VERSION 5.7 ;
BUSBITCHARS "[]" ;
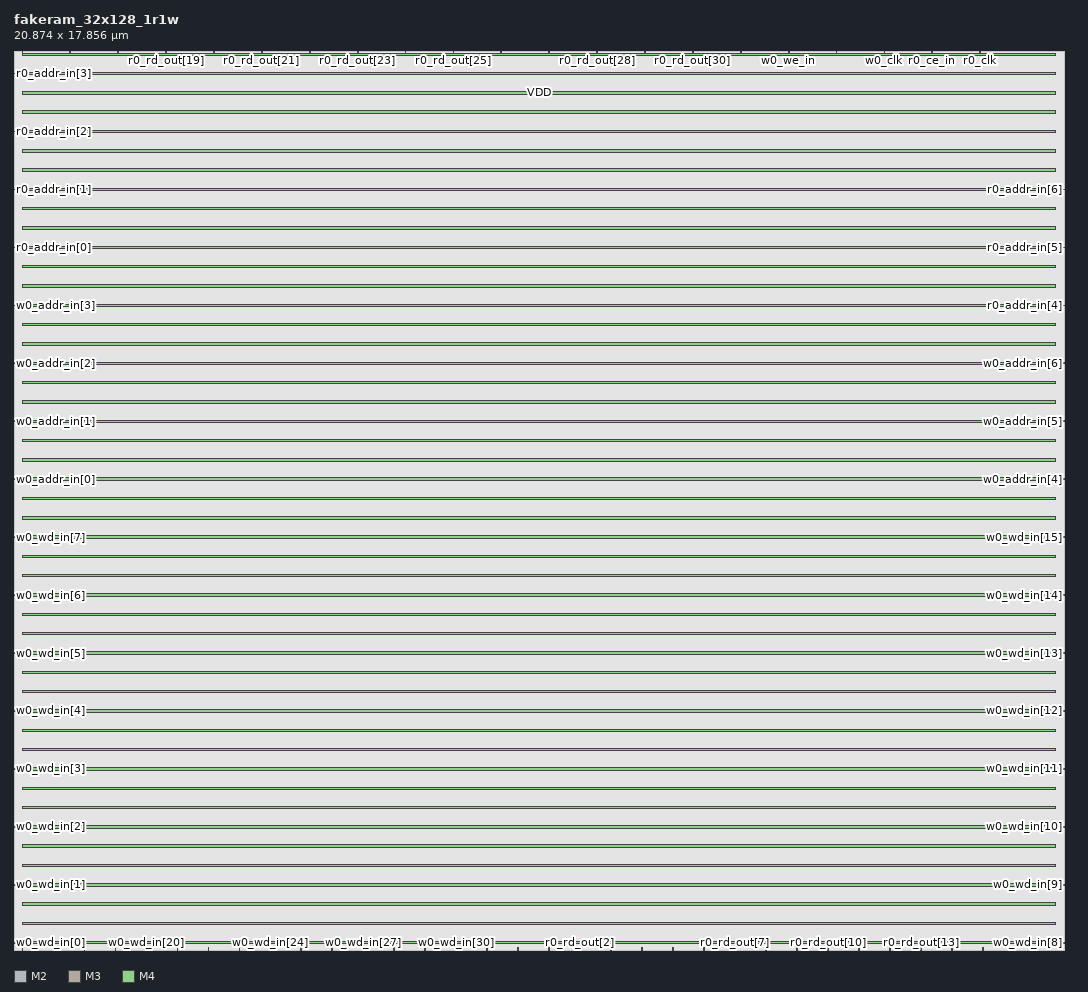
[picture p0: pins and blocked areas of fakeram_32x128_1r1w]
MACRO fakeram_32x128_1r1w
  FOREIGN fakeram_32x128_1r1w 0 0 ;
  SYMMETRY X Y R90 ;
  SIZE 20.874 BY 17.856 ;
  CLASS BLOCK ;
  PIN w0_wd_in[0]
    DIRECTION INPUT ;
    USE SIGNAL ;
    SHAPE ABUTMENT ;
    PORT
      LAYER M2 ;
      RECT 0.000 0.138 0.036 0.150 ;
    END
  END w0_wd_in[0]
  PIN w0_wd_in[1]
    DIRECTION INPUT ;
    USE SIGNAL ;
    SHAPE ABUTMENT ;
    PORT
      LAYER M2 ;
      RECT 0.000 1.290 0.036 1.302 ;
    END
  END w0_wd_in[1]
  PIN w0_wd_in[2]
    DIRECTION INPUT ;
    USE SIGNAL ;
    SHAPE ABUTMENT ;
    PORT
      LAYER M2 ;
      RECT 0.000 2.442 0.036 2.454 ;
    END
  END w0_wd_in[2]
  PIN w0_wd_in[3]
    DIRECTION INPUT ;
    USE SIGNAL ;
    SHAPE ABUTMENT ;
    PORT
      LAYER M2 ;
      RECT 0.000 3.594 0.036 3.606 ;
    END
  END w0_wd_in[3]
  PIN w0_wd_in[4]
    DIRECTION INPUT ;
    USE SIGNAL ;
    SHAPE ABUTMENT ;
    PORT
      LAYER M2 ;
      RECT 0.000 4.746 0.036 4.758 ;
    END
  END w0_wd_in[4]
  PIN w0_wd_in[5]
    DIRECTION INPUT ;
    USE SIGNAL ;
    SHAPE ABUTMENT ;
    PORT
      LAYER M2 ;
      RECT 0.000 5.898 0.036 5.910 ;
    END
  END w0_wd_in[5]
  PIN w0_wd_in[6]
    DIRECTION INPUT ;
    USE SIGNAL ;
    SHAPE ABUTMENT ;
    PORT
      LAYER M2 ;
      RECT 0.000 7.050 0.036 7.062 ;
    END
  END w0_wd_in[6]
  PIN w0_wd_in[7]
    DIRECTION INPUT ;
    USE SIGNAL ;
    SHAPE ABUTMENT ;
    PORT
      LAYER M2 ;
      RECT 0.000 8.202 0.036 8.214 ;
    END
  END w0_wd_in[7]
  PIN w0_wd_in[8]
    DIRECTION INPUT ;
    USE SIGNAL ;
    SHAPE ABUTMENT ;
    PORT
      LAYER M2 ;
      RECT 20.838 0.138 20.874 0.150 ;
    END
  END w0_wd_in[8]
  PIN w0_wd_in[9]
    DIRECTION INPUT ;
    USE SIGNAL ;
    SHAPE ABUTMENT ;
    PORT
      LAYER M2 ;
      RECT 20.838 1.290 20.874 1.302 ;
    END
  END w0_wd_in[9]
  PIN w0_wd_in[10]
    DIRECTION INPUT ;
    USE SIGNAL ;
    SHAPE ABUTMENT ;
    PORT
      LAYER M2 ;
      RECT 20.838 2.442 20.874 2.454 ;
    END
  END w0_wd_in[10]
  PIN w0_wd_in[11]
    DIRECTION INPUT ;
    USE SIGNAL ;
    SHAPE ABUTMENT ;
    PORT
      LAYER M2 ;
      RECT 20.838 3.594 20.874 3.606 ;
    END
  END w0_wd_in[11]
  PIN w0_wd_in[12]
    DIRECTION INPUT ;
    USE SIGNAL ;
    SHAPE ABUTMENT ;
    PORT
      LAYER M2 ;
      RECT 20.838 4.746 20.874 4.758 ;
    END
  END w0_wd_in[12]
  PIN w0_wd_in[13]
    DIRECTION INPUT ;
    USE SIGNAL ;
    SHAPE ABUTMENT ;
    PORT
      LAYER M2 ;
      RECT 20.838 5.898 20.874 5.910 ;
    END
  END w0_wd_in[13]
  PIN w0_wd_in[14]
    DIRECTION INPUT ;
    USE SIGNAL ;
    SHAPE ABUTMENT ;
    PORT
      LAYER M2 ;
      RECT 20.838 7.050 20.874 7.062 ;
    END
  END w0_wd_in[14]
  PIN w0_wd_in[15]
    DIRECTION INPUT ;
    USE SIGNAL ;
    SHAPE ABUTMENT ;
    PORT
      LAYER M2 ;
      RECT 20.838 8.202 20.874 8.214 ;
    END
  END w0_wd_in[15]
  PIN w0_wd_in[16]
    DIRECTION INPUT ;
    USE SIGNAL ;
    SHAPE ABUTMENT ;
    PORT
      LAYER M3 ;
      RECT 0.161 0.000 0.175 0.042 ;
    END
  END w0_wd_in[16]
  PIN w0_wd_in[17]
    DIRECTION INPUT ;
    USE SIGNAL ;
    SHAPE ABUTMENT ;
    PORT
      LAYER M3 ;
      RECT 0.777 0.000 0.791 0.042 ;
    END
  END w0_wd_in[17]
  PIN w0_wd_in[18]
    DIRECTION INPUT ;
    USE SIGNAL ;
    SHAPE ABUTMENT ;
    PORT
      LAYER M3 ;
      RECT 1.393 0.000 1.407 0.042 ;
    END
  END w0_wd_in[18]
  PIN w0_wd_in[19]
    DIRECTION INPUT ;
    USE SIGNAL ;
    SHAPE ABUTMENT ;
    PORT
      LAYER M3 ;
      RECT 2.009 0.000 2.023 0.042 ;
    END
  END w0_wd_in[19]
  PIN w0_wd_in[20]
    DIRECTION INPUT ;
    USE SIGNAL ;
    SHAPE ABUTMENT ;
    PORT
      LAYER M3 ;
      RECT 2.625 0.000 2.639 0.042 ;
    END
  END w0_wd_in[20]
  PIN w0_wd_in[21]
    DIRECTION INPUT ;
    USE SIGNAL ;
    SHAPE ABUTMENT ;
    PORT
      LAYER M3 ;
      RECT 3.241 0.000 3.255 0.042 ;
    END
  END w0_wd_in[21]
  PIN w0_wd_in[22]
    DIRECTION INPUT ;
    USE SIGNAL ;
    SHAPE ABUTMENT ;
    PORT
      LAYER M3 ;
      RECT 3.857 0.000 3.871 0.042 ;
    END
  END w0_wd_in[22]
  PIN w0_wd_in[23]
    DIRECTION INPUT ;
    USE SIGNAL ;
    SHAPE ABUTMENT ;
    PORT
      LAYER M3 ;
      RECT 4.473 0.000 4.487 0.042 ;
    END
  END w0_wd_in[23]
  PIN w0_wd_in[24]
    DIRECTION INPUT ;
    USE SIGNAL ;
    SHAPE ABUTMENT ;
    PORT
      LAYER M3 ;
      RECT 5.089 0.000 5.103 0.042 ;
    END
  END w0_wd_in[24]
  PIN w0_wd_in[25]
    DIRECTION INPUT ;
    USE SIGNAL ;
    SHAPE ABUTMENT ;
    PORT
      LAYER M3 ;
      RECT 5.705 0.000 5.719 0.042 ;
    END
  END w0_wd_in[25]
  PIN w0_wd_in[26]
    DIRECTION INPUT ;
    USE SIGNAL ;
    SHAPE ABUTMENT ;
    PORT
      LAYER M3 ;
      RECT 6.321 0.000 6.335 0.042 ;
    END
  END w0_wd_in[26]
  PIN w0_wd_in[27]
    DIRECTION INPUT ;
    USE SIGNAL ;
    SHAPE ABUTMENT ;
    PORT
      LAYER M3 ;
      RECT 6.937 0.000 6.951 0.042 ;
    END
  END w0_wd_in[27]
  PIN w0_wd_in[28]
    DIRECTION INPUT ;
    USE SIGNAL ;
    SHAPE ABUTMENT ;
    PORT
      LAYER M3 ;
      RECT 7.553 0.000 7.567 0.042 ;
    END
  END w0_wd_in[28]
  PIN w0_wd_in[29]
    DIRECTION INPUT ;
    USE SIGNAL ;
    SHAPE ABUTMENT ;
    PORT
      LAYER M3 ;
      RECT 8.169 0.000 8.183 0.042 ;
    END
  END w0_wd_in[29]
  PIN w0_wd_in[30]
    DIRECTION INPUT ;
    USE SIGNAL ;
    SHAPE ABUTMENT ;
    PORT
      LAYER M3 ;
      RECT 8.785 0.000 8.799 0.042 ;
    END
  END w0_wd_in[30]
  PIN w0_wd_in[31]
    DIRECTION INPUT ;
    USE SIGNAL ;
    SHAPE ABUTMENT ;
    PORT
      LAYER M3 ;
      RECT 9.401 0.000 9.415 0.042 ;
    END
  END w0_wd_in[31]
  PIN r0_rd_out[0]
    DIRECTION OUTPUT ;
    USE SIGNAL ;
    SHAPE ABUTMENT ;
    PORT
      LAYER M3 ;
      RECT 10.017 0.000 10.031 0.042 ;
    END
  END r0_rd_out[0]
  PIN r0_rd_out[1]
    DIRECTION OUTPUT ;
    USE SIGNAL ;
    SHAPE ABUTMENT ;
    PORT
      LAYER M3 ;
      RECT 10.633 0.000 10.647 0.042 ;
    END
  END r0_rd_out[1]
  PIN r0_rd_out[2]
    DIRECTION OUTPUT ;
    USE SIGNAL ;
    SHAPE ABUTMENT ;
    PORT
      LAYER M3 ;
      RECT 11.249 0.000 11.263 0.042 ;
    END
  END r0_rd_out[2]
  PIN r0_rd_out[3]
    DIRECTION OUTPUT ;
    USE SIGNAL ;
    SHAPE ABUTMENT ;
    PORT
      LAYER M3 ;
      RECT 11.865 0.000 11.879 0.042 ;
    END
  END r0_rd_out[3]
  PIN r0_rd_out[4]
    DIRECTION OUTPUT ;
    USE SIGNAL ;
    SHAPE ABUTMENT ;
    PORT
      LAYER M3 ;
      RECT 12.481 0.000 12.495 0.042 ;
    END
  END r0_rd_out[4]
  PIN r0_rd_out[5]
    DIRECTION OUTPUT ;
    USE SIGNAL ;
    SHAPE ABUTMENT ;
    PORT
      LAYER M3 ;
      RECT 13.097 0.000 13.111 0.042 ;
    END
  END r0_rd_out[5]
  PIN r0_rd_out[6]
    DIRECTION OUTPUT ;
    USE SIGNAL ;
    SHAPE ABUTMENT ;
    PORT
      LAYER M3 ;
      RECT 13.713 0.000 13.727 0.042 ;
    END
  END r0_rd_out[6]
  PIN r0_rd_out[7]
    DIRECTION OUTPUT ;
    USE SIGNAL ;
    SHAPE ABUTMENT ;
    PORT
      LAYER M3 ;
      RECT 14.329 0.000 14.343 0.042 ;
    END
  END r0_rd_out[7]
  PIN r0_rd_out[8]
    DIRECTION OUTPUT ;
    USE SIGNAL ;
    SHAPE ABUTMENT ;
    PORT
      LAYER M3 ;
      RECT 14.945 0.000 14.959 0.042 ;
    END
  END r0_rd_out[8]
  PIN r0_rd_out[9]
    DIRECTION OUTPUT ;
    USE SIGNAL ;
    SHAPE ABUTMENT ;
    PORT
      LAYER M3 ;
      RECT 15.561 0.000 15.575 0.042 ;
    END
  END r0_rd_out[9]
  PIN r0_rd_out[10]
    DIRECTION OUTPUT ;
    USE SIGNAL ;
    SHAPE ABUTMENT ;
    PORT
      LAYER M3 ;
      RECT 16.177 0.000 16.191 0.042 ;
    END
  END r0_rd_out[10]
  PIN r0_rd_out[11]
    DIRECTION OUTPUT ;
    USE SIGNAL ;
    SHAPE ABUTMENT ;
    PORT
      LAYER M3 ;
      RECT 16.793 0.000 16.807 0.042 ;
    END
  END r0_rd_out[11]
  PIN r0_rd_out[12]
    DIRECTION OUTPUT ;
    USE SIGNAL ;
    SHAPE ABUTMENT ;
    PORT
      LAYER M3 ;
      RECT 17.409 0.000 17.423 0.042 ;
    END
  END r0_rd_out[12]
  PIN r0_rd_out[13]
    DIRECTION OUTPUT ;
    USE SIGNAL ;
    SHAPE ABUTMENT ;
    PORT
      LAYER M3 ;
      RECT 18.025 0.000 18.039 0.042 ;
    END
  END r0_rd_out[13]
  PIN r0_rd_out[14]
    DIRECTION OUTPUT ;
    USE SIGNAL ;
    SHAPE ABUTMENT ;
    PORT
      LAYER M3 ;
      RECT 18.641 0.000 18.655 0.042 ;
    END
  END r0_rd_out[14]
  PIN r0_rd_out[15]
    DIRECTION OUTPUT ;
    USE SIGNAL ;
    SHAPE ABUTMENT ;
    PORT
      LAYER M3 ;
      RECT 19.257 0.000 19.271 0.042 ;
    END
  END r0_rd_out[15]
  PIN r0_rd_out[16]
    DIRECTION OUTPUT ;
    USE SIGNAL ;
    SHAPE ABUTMENT ;
    PORT
      LAYER M3 ;
      RECT 0.161 17.814 0.175 17.856 ;
    END
  END r0_rd_out[16]
  PIN r0_rd_out[17]
    DIRECTION OUTPUT ;
    USE SIGNAL ;
    SHAPE ABUTMENT ;
    PORT
      LAYER M3 ;
      RECT 1.113 17.814 1.127 17.856 ;
    END
  END r0_rd_out[17]
  PIN r0_rd_out[18]
    DIRECTION OUTPUT ;
    USE SIGNAL ;
    SHAPE ABUTMENT ;
    PORT
      LAYER M3 ;
      RECT 2.065 17.814 2.079 17.856 ;
    END
  END r0_rd_out[18]
  PIN r0_rd_out[19]
    DIRECTION OUTPUT ;
    USE SIGNAL ;
    SHAPE ABUTMENT ;
    PORT
      LAYER M3 ;
      RECT 3.017 17.814 3.031 17.856 ;
    END
  END r0_rd_out[19]
  PIN r0_rd_out[20]
    DIRECTION OUTPUT ;
    USE SIGNAL ;
    SHAPE ABUTMENT ;
    PORT
      LAYER M3 ;
      RECT 3.969 17.814 3.983 17.856 ;
    END
  END r0_rd_out[20]
  PIN r0_rd_out[21]
    DIRECTION OUTPUT ;
    USE SIGNAL ;
    SHAPE ABUTMENT ;
    PORT
      LAYER M3 ;
      RECT 4.921 17.814 4.935 17.856 ;
    END
  END r0_rd_out[21]
  PIN r0_rd_out[22]
    DIRECTION OUTPUT ;
    USE SIGNAL ;
    SHAPE ABUTMENT ;
    PORT
      LAYER M3 ;
      RECT 5.873 17.814 5.887 17.856 ;
    END
  END r0_rd_out[22]
  PIN r0_rd_out[23]
    DIRECTION OUTPUT ;
    USE SIGNAL ;
    SHAPE ABUTMENT ;
    PORT
      LAYER M3 ;
      RECT 6.825 17.814 6.839 17.856 ;
    END
  END r0_rd_out[23]
  PIN r0_rd_out[24]
    DIRECTION OUTPUT ;
    USE SIGNAL ;
    SHAPE ABUTMENT ;
    PORT
      LAYER M3 ;
      RECT 7.777 17.814 7.791 17.856 ;
    END
  END r0_rd_out[24]
  PIN r0_rd_out[25]
    DIRECTION OUTPUT ;
    USE SIGNAL ;
    SHAPE ABUTMENT ;
    PORT
      LAYER M3 ;
      RECT 8.729 17.814 8.743 17.856 ;
    END
  END r0_rd_out[25]
  PIN r0_rd_out[26]
    DIRECTION OUTPUT ;
    USE SIGNAL ;
    SHAPE ABUTMENT ;
    PORT
      LAYER M3 ;
      RECT 9.681 17.814 9.695 17.856 ;
    END
  END r0_rd_out[26]
  PIN r0_rd_out[27]
    DIRECTION OUTPUT ;
    USE SIGNAL ;
    SHAPE ABUTMENT ;
    PORT
      LAYER M3 ;
      RECT 10.633 17.814 10.647 17.856 ;
    END
  END r0_rd_out[27]
  PIN r0_rd_out[28]
    DIRECTION OUTPUT ;
    USE SIGNAL ;
    SHAPE ABUTMENT ;
    PORT
      LAYER M3 ;
      RECT 11.585 17.814 11.599 17.856 ;
    END
  END r0_rd_out[28]
  PIN r0_rd_out[29]
    DIRECTION OUTPUT ;
    USE SIGNAL ;
    SHAPE ABUTMENT ;
    PORT
      LAYER M3 ;
      RECT 12.537 17.814 12.551 17.856 ;
    END
  END r0_rd_out[29]
  PIN r0_rd_out[30]
    DIRECTION OUTPUT ;
    USE SIGNAL ;
    SHAPE ABUTMENT ;
    PORT
      LAYER M3 ;
      RECT 13.489 17.814 13.503 17.856 ;
    END
  END r0_rd_out[30]
  PIN r0_rd_out[31]
    DIRECTION OUTPUT ;
    USE SIGNAL ;
    SHAPE ABUTMENT ;
    PORT
      LAYER M3 ;
      RECT 14.441 17.814 14.455 17.856 ;
    END
  END r0_rd_out[31]
  PIN w0_addr_in[0]
    DIRECTION INPUT ;
    USE SIGNAL ;
    SHAPE ABUTMENT ;
    PORT
      LAYER M2 ;
      RECT 0.000 9.354 0.036 9.366 ;
    END
  END w0_addr_in[0]
  PIN w0_addr_in[1]
    DIRECTION INPUT ;
    USE SIGNAL ;
    SHAPE ABUTMENT ;
    PORT
      LAYER M2 ;
      RECT 0.000 10.506 0.036 10.518 ;
    END
  END w0_addr_in[1]
  PIN w0_addr_in[2]
    DIRECTION INPUT ;
    USE SIGNAL ;
    SHAPE ABUTMENT ;
    PORT
      LAYER M2 ;
      RECT 0.000 11.658 0.036 11.670 ;
    END
  END w0_addr_in[2]
  PIN w0_addr_in[3]
    DIRECTION INPUT ;
    USE SIGNAL ;
    SHAPE ABUTMENT ;
    PORT
      LAYER M2 ;
      RECT 0.000 12.810 0.036 12.822 ;
    END
  END w0_addr_in[3]
  PIN w0_addr_in[4]
    DIRECTION INPUT ;
    USE SIGNAL ;
    SHAPE ABUTMENT ;
    PORT
      LAYER M2 ;
      RECT 20.838 9.354 20.874 9.366 ;
    END
  END w0_addr_in[4]
  PIN w0_addr_in[5]
    DIRECTION INPUT ;
    USE SIGNAL ;
    SHAPE ABUTMENT ;
    PORT
      LAYER M2 ;
      RECT 20.838 10.506 20.874 10.518 ;
    END
  END w0_addr_in[5]
  PIN w0_addr_in[6]
    DIRECTION INPUT ;
    USE SIGNAL ;
    SHAPE ABUTMENT ;
    PORT
      LAYER M2 ;
      RECT 20.838 11.658 20.874 11.670 ;
    END
  END w0_addr_in[6]
  PIN r0_addr_in[0]
    DIRECTION INPUT ;
    USE SIGNAL ;
    SHAPE ABUTMENT ;
    PORT
      LAYER M2 ;
      RECT 0.000 13.962 0.036 13.974 ;
    END
  END r0_addr_in[0]
  PIN r0_addr_in[1]
    DIRECTION INPUT ;
    USE SIGNAL ;
    SHAPE ABUTMENT ;
    PORT
      LAYER M2 ;
      RECT 0.000 15.114 0.036 15.126 ;
    END
  END r0_addr_in[1]
  PIN r0_addr_in[2]
    DIRECTION INPUT ;
    USE SIGNAL ;
    SHAPE ABUTMENT ;
    PORT
      LAYER M2 ;
      RECT 0.000 16.266 0.036 16.278 ;
    END
  END r0_addr_in[2]
  PIN r0_addr_in[3]
    DIRECTION INPUT ;
    USE SIGNAL ;
    SHAPE ABUTMENT ;
    PORT
      LAYER M2 ;
      RECT 0.000 17.418 0.036 17.430 ;
    END
  END r0_addr_in[3]
  PIN r0_addr_in[4]
    DIRECTION INPUT ;
    USE SIGNAL ;
    SHAPE ABUTMENT ;
    PORT
      LAYER M2 ;
      RECT 20.838 12.810 20.874 12.822 ;
    END
  END r0_addr_in[4]
  PIN r0_addr_in[5]
    DIRECTION INPUT ;
    USE SIGNAL ;
    SHAPE ABUTMENT ;
    PORT
      LAYER M2 ;
      RECT 20.838 13.962 20.874 13.974 ;
    END
  END r0_addr_in[5]
  PIN r0_addr_in[6]
    DIRECTION INPUT ;
    USE SIGNAL ;
    SHAPE ABUTMENT ;
    PORT
      LAYER M2 ;
      RECT 20.838 15.114 20.874 15.126 ;
    END
  END r0_addr_in[6]
  PIN w0_we_in
    DIRECTION INPUT ;
    USE SIGNAL ;
    SHAPE ABUTMENT ;
    PORT
      LAYER M3 ;
      RECT 15.393 17.814 15.407 17.856 ;
    END
  END w0_we_in
  PIN w0_ce_in
    DIRECTION INPUT ;
    USE SIGNAL ;
    SHAPE ABUTMENT ;
    PORT
      LAYER M3 ;
      RECT 16.345 17.814 16.359 17.856 ;
    END
  END w0_ce_in
  PIN w0_clk
    DIRECTION INPUT ;
    USE SIGNAL ;
    SHAPE ABUTMENT ;
    PORT
      LAYER M3 ;
      RECT 17.297 17.814 17.311 17.856 ;
    END
  END w0_clk
  PIN r0_ce_in
    DIRECTION INPUT ;
    USE SIGNAL ;
    SHAPE ABUTMENT ;
    PORT
      LAYER M3 ;
      RECT 18.249 17.814 18.263 17.856 ;
    END
  END r0_ce_in
  PIN r0_clk
    DIRECTION INPUT ;
    USE SIGNAL ;
    SHAPE ABUTMENT ;
    PORT
      LAYER M3 ;
      RECT 19.201 17.814 19.215 17.856 ;
    END
  END r0_clk
  PIN VSS
    DIRECTION INOUT ;
    USE GROUND ;
    PORT
      LAYER M4 ;
      RECT 0.168 0.120 20.706 0.168 ;
      RECT 0.168 0.504 20.706 0.552 ;
      RECT 0.168 0.888 20.706 0.936 ;
      RECT 0.168 1.272 20.706 1.320 ;
      RECT 0.168 1.656 20.706 1.704 ;
      RECT 0.168 2.040 20.706 2.088 ;
      RECT 0.168 2.424 20.706 2.472 ;
      RECT 0.168 2.808 20.706 2.856 ;
      RECT 0.168 3.192 20.706 3.240 ;
      RECT 0.168 3.576 20.706 3.624 ;
      RECT 0.168 3.960 20.706 4.008 ;
      RECT 0.168 4.344 20.706 4.392 ;
      RECT 0.168 4.728 20.706 4.776 ;
      RECT 0.168 5.112 20.706 5.160 ;
      RECT 0.168 5.496 20.706 5.544 ;
      RECT 0.168 5.880 20.706 5.928 ;
      RECT 0.168 6.264 20.706 6.312 ;
      RECT 0.168 6.648 20.706 6.696 ;
      RECT 0.168 7.032 20.706 7.080 ;
      RECT 0.168 7.416 20.706 7.464 ;
      RECT 0.168 7.800 20.706 7.848 ;
      RECT 0.168 8.184 20.706 8.232 ;
      RECT 0.168 8.568 20.706 8.616 ;
      RECT 0.168 8.952 20.706 9.000 ;
      RECT 0.168 9.336 20.706 9.384 ;
      RECT 0.168 9.720 20.706 9.768 ;
      RECT 0.168 10.104 20.706 10.152 ;
      RECT 0.168 10.488 20.706 10.536 ;
      RECT 0.168 10.872 20.706 10.920 ;
      RECT 0.168 11.256 20.706 11.304 ;
      RECT 0.168 11.640 20.706 11.688 ;
      RECT 0.168 12.024 20.706 12.072 ;
      RECT 0.168 12.408 20.706 12.456 ;
      RECT 0.168 12.792 20.706 12.840 ;
      RECT 0.168 13.176 20.706 13.224 ;
      RECT 0.168 13.560 20.706 13.608 ;
      RECT 0.168 13.944 20.706 13.992 ;
      RECT 0.168 14.328 20.706 14.376 ;
      RECT 0.168 14.712 20.706 14.760 ;
      RECT 0.168 15.096 20.706 15.144 ;
      RECT 0.168 15.480 20.706 15.528 ;
      RECT 0.168 15.864 20.706 15.912 ;
      RECT 0.168 16.248 20.706 16.296 ;
      RECT 0.168 16.632 20.706 16.680 ;
      RECT 0.168 17.016 20.706 17.064 ;
      RECT 0.168 17.400 20.706 17.448 ;
      RECT 0.168 17.784 20.706 17.832 ;
    END
  END VSS
  PIN VDD
    DIRECTION INOUT ;
    USE POWER ;
    PORT
      LAYER M4 ;
      RECT 0.168 0.120 20.706 0.168 ;
      RECT 0.168 0.504 20.706 0.552 ;
      RECT 0.168 0.888 20.706 0.936 ;
      RECT 0.168 1.272 20.706 1.320 ;
      RECT 0.168 1.656 20.706 1.704 ;
      RECT 0.168 2.040 20.706 2.088 ;
      RECT 0.168 2.424 20.706 2.472 ;
      RECT 0.168 2.808 20.706 2.856 ;
      RECT 0.168 3.192 20.706 3.240 ;
      RECT 0.168 3.576 20.706 3.624 ;
      RECT 0.168 3.960 20.706 4.008 ;
      RECT 0.168 4.344 20.706 4.392 ;
      RECT 0.168 4.728 20.706 4.776 ;
      RECT 0.168 5.112 20.706 5.160 ;
      RECT 0.168 5.496 20.706 5.544 ;
      RECT 0.168 5.880 20.706 5.928 ;
      RECT 0.168 6.264 20.706 6.312 ;
      RECT 0.168 6.648 20.706 6.696 ;
      RECT 0.168 7.032 20.706 7.080 ;
      RECT 0.168 7.416 20.706 7.464 ;
      RECT 0.168 7.800 20.706 7.848 ;
      RECT 0.168 8.184 20.706 8.232 ;
      RECT 0.168 8.568 20.706 8.616 ;
      RECT 0.168 8.952 20.706 9.000 ;
      RECT 0.168 9.336 20.706 9.384 ;
      RECT 0.168 9.720 20.706 9.768 ;
      RECT 0.168 10.104 20.706 10.152 ;
      RECT 0.168 10.488 20.706 10.536 ;
      RECT 0.168 10.872 20.706 10.920 ;
      RECT 0.168 11.256 20.706 11.304 ;
      RECT 0.168 11.640 20.706 11.688 ;
      RECT 0.168 12.024 20.706 12.072 ;
      RECT 0.168 12.408 20.706 12.456 ;
      RECT 0.168 12.792 20.706 12.840 ;
      RECT 0.168 13.176 20.706 13.224 ;
      RECT 0.168 13.560 20.706 13.608 ;
      RECT 0.168 13.944 20.706 13.992 ;
      RECT 0.168 14.328 20.706 14.376 ;
      RECT 0.168 14.712 20.706 14.760 ;
      RECT 0.168 15.096 20.706 15.144 ;
      RECT 0.168 15.480 20.706 15.528 ;
      RECT 0.168 15.864 20.706 15.912 ;
      RECT 0.168 16.248 20.706 16.296 ;
      RECT 0.168 16.632 20.706 16.680 ;
      RECT 0.168 17.016 20.706 17.064 ;
      RECT 0.168 17.400 20.706 17.448 ;
      RECT 0.168 17.784 20.706 17.832 ;
    END
  END VDD
  OBS
    LAYER M1 ;
    RECT 0 0 20.874 17.856 ;
    LAYER M2 ;
    RECT 0 0 20.874 17.856 ;
    LAYER M3 ;
    RECT 0 0 20.874 17.856 ;
    LAYER M4 ;
    RECT 0 0 20.874 17.856 ;
  END
END fakeram_32x128_1r1w

END LIBRARY
